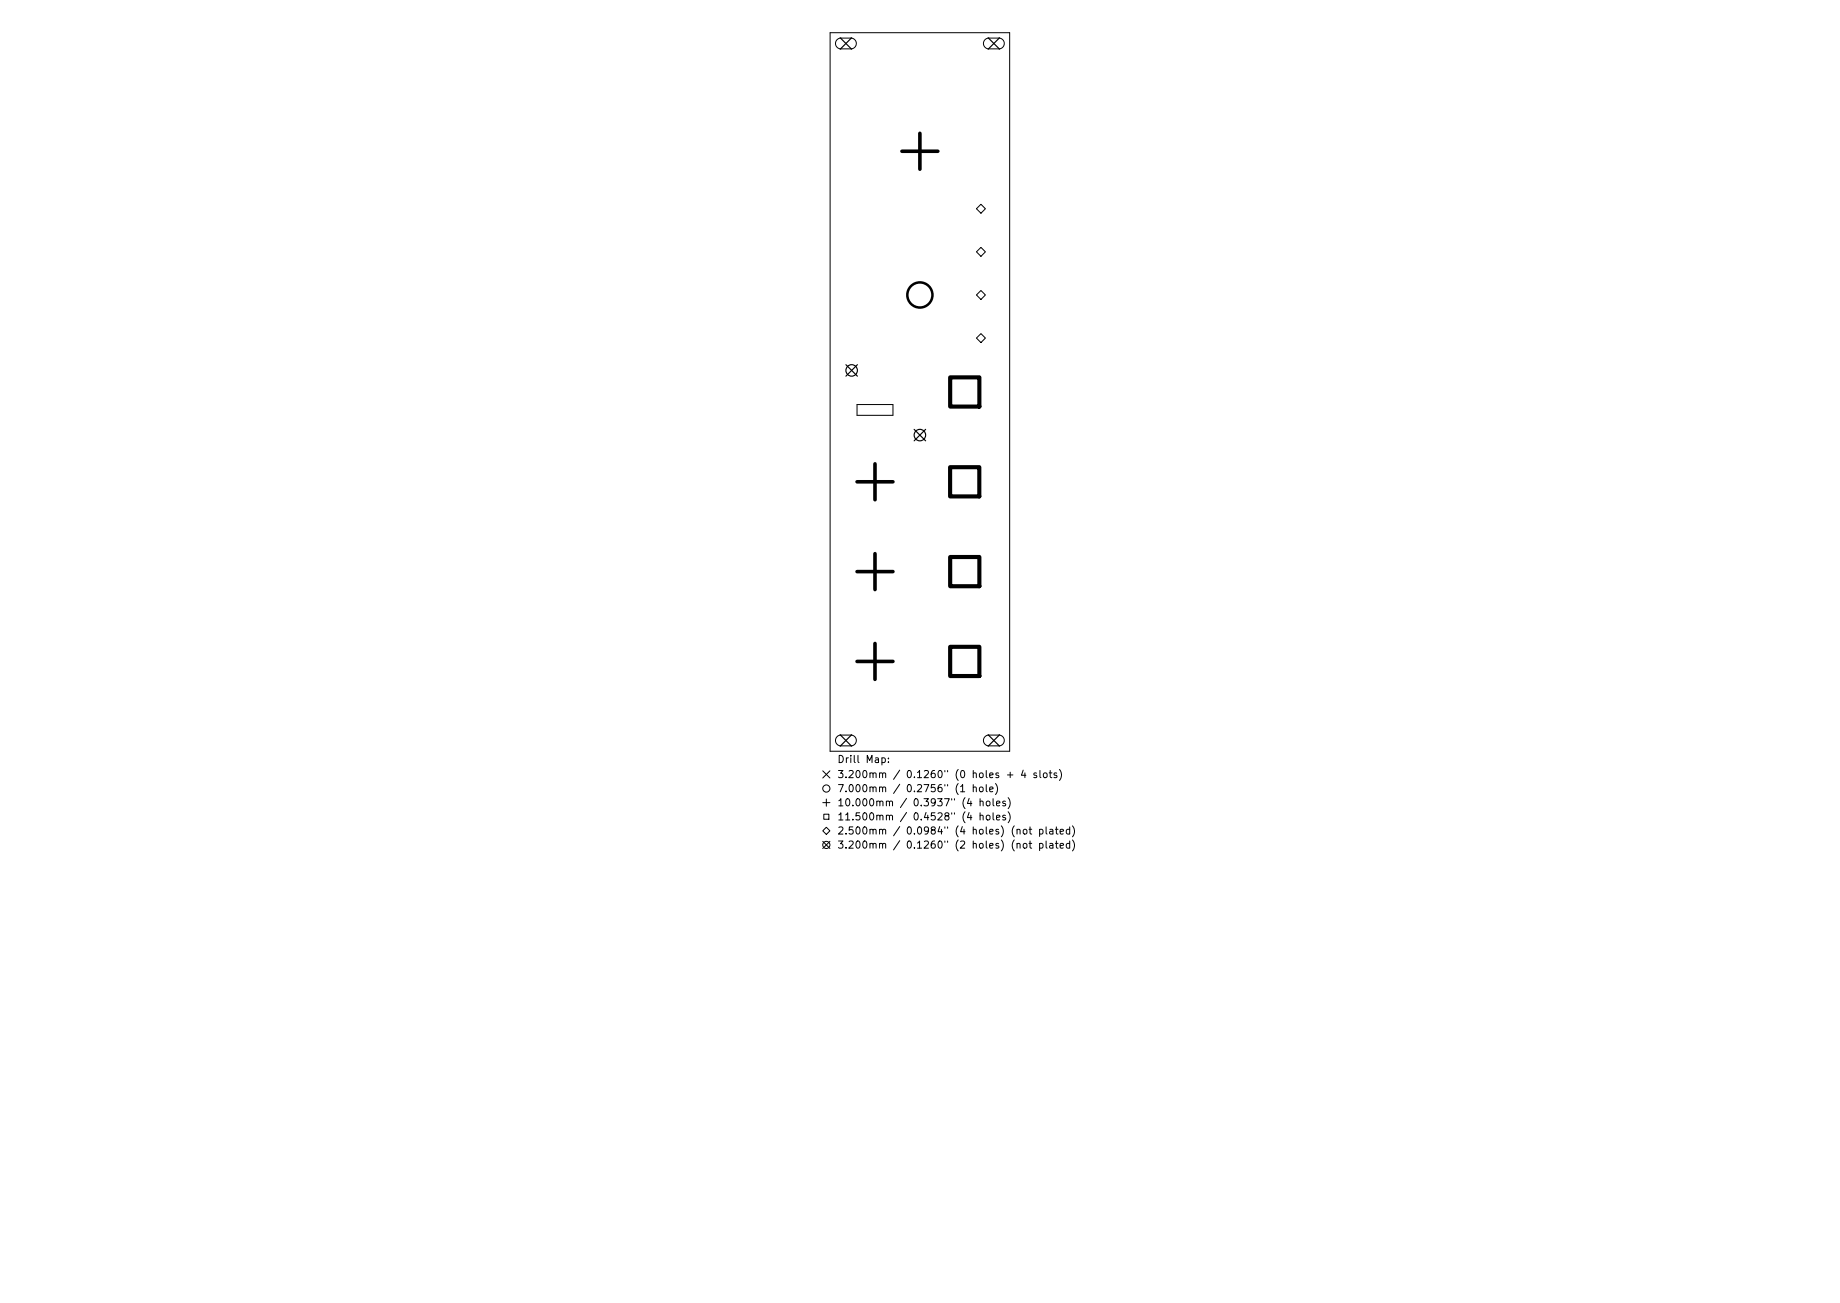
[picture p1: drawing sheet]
<svg xmlns="http://www.w3.org/2000/svg" width="297mm" height="210mm" viewBox="0 0 297 210" stroke-linecap="round" stroke-linejoin="round" font-family="sans-serif">
<defs><g id="words">
<g font-size="1.6">
<text x="135.1" y="123.1">Drill Map:</text>
<text x="135.1" y="125.5">3.200mm / 0.1260&quot; (0 holes + 4 slots)</text>
<text x="135.1" y="127.8">7.000mm / 0.2756&quot; (1 hole)</text>
<text x="135.1" y="130.1">10.000mm / 0.3937&quot; (4 holes)</text>
<text x="135.1" y="132.4">11.500mm / 0.4528&quot; (4 holes)</text>
<text x="135.1" y="134.6">2.500mm / 0.0984&quot; (4 holes) (not plated)</text>
<text x="135.1" y="136.9">3.200mm / 0.1260&quot; (2 holes) (not plated)</text>
</g>
</g></defs>
<g fill="none" stroke="#000" stroke-width=".16">
<path d="M134 5.3h29v115.9h-29zM135.1 6.4l.6-.2 1.7-.1a.87 .87 0 0 1 .8 .9 .87 .87 0 0 1-.8 .9h-1.7a.87 .87 0 0 1-.8-.6 .87 .87 0 0 1 .2-.9zM159 6.4l.6-.2 1.7-.1a.87 .87 0 0 1 .8 .9 .87 .87 0 0 1-.8 .9h-1.7a.87 .87 0 0 1-.8-.6 .87 .87 0 0 1 .2-.9zM158.4 33l.7 .7-.7 .7-.8-.7zM158.4 39.9l.7 .7-.7 .8-.8-.8zM157.6 54.6l.8-.8 .7 .8-.7 .7zM158.4 46.9l.7 .7-.7 .7-.8-.7zM138.4 65.3h5.8v1.7h-5.8zM135.1 118.9l.6-.3h1.7a.87 .87 0 0 1 .8 .9 .87 .87 0 0 1-.8 .9h-1.7a.87 .87 0 0 1-.8-.6 .87 .87 0 0 1 .2-.9zM159 118.9l.6-.3h1.7a.87 .87 0 0 1 .8 .9 .87 .87 0 0 1-.8 .9h-1.7a.87 .87 0 0 1-.8-.6 .87 .87 0 0 1 .2-.9zM132.8 124.4l1.2 1.1M132.8 129.5h1.2"/>
<path d="M132.8 135.8l1.2 1.1M133 131.4h.8v.8h-.8zM133.4 133.5l.6 .6-.6 .5-.6-.5zM133.4 128.9v1.2M134 124.4l-1.2 1.1M134 135.8l-1.2 1.1M142.4 122.3h.3l.2 .2-.1 .5h-.4M143.4 122.9v.2M143.4 122.3v.1M155.1 126.9l.3-.3v1.2M155.1 127.8h.6M156.5 128.8l-.3 .9h.7"/>
<path d="M156.5 131.1l-.3 .8h.7M157.1 127.1l.2-.1h.3v.8M157.1 126.6v1.2M158.2 127.1l.1-.1 .4 .1v.4l-.1 .2-.3 .1-.1-.1zM158.2 129.4l.2-.1h.3v.7M158.2 131.7l.2-.2 .3 .1v.7M158.2 128.9v1.1M158.2 131.2v1.1M159.2 126.6v1l.2 .2M159.3 129.3h.3l.2 .2v.3l-.2 .2h-.3l-.1-.2zM159.3 131.6l.3-.1 .2 .3v.3l-.2 .2h-.3l-.1-.2zM159.8 127.4l.5-.1v-.3h-.4l-.1 .2v.5h.5"/>
<path d="M160.3 128.9v1l.2 .1M160.3 131.2v.9l.2 .2M160.7 126.4a1.33 1.33 0 0 1 0 1.8M160.9 129.7l.5-.2v-.2h-.4l-.1 .1v.6h.5M160.9 131.9l.5-.1v-.2l-.4-.1-.1 .2v.6h.5M162.3 129.3h-.3l-.1 .1v.2l.4 .1v.3h-.4M162.3 131.6l-.3-.1-.1 .2v.2l.4 .1v.3h-.4M162.6 125h.9M162.7 128.7a1.33 1.33 0 0 1 0 1.8M162.7 131a1.33 1.33 0 0 1 0 1.8M163.1 124.6v.9M164.2 133.9l.1-.1 .3 .1 .1 .7"/>
<path d="M164.2 136.2l.1-.1h.3l.1 .8M165.2 124.3l-.3 .8h.7M165.2 133.9l.2-.1 .3 .1 .1 .5-.1 .1-.3 .1-.2-.1zM165.2 136.2l.2-.1 .3 .1 .1 .4-.1 .2-.3 .1-.2-.1zM165.5 124.7v.8M166.1 133.8h.5M166.1 136.1h.5M166.3 133.4v1l.3 .2M166.3 135.7v1l.3 .2M167.3 124.8l-.2-.1-.2 .2v.1l.4 .2v.2h-.4M167.8 133.9l.4-.1 .2 .2-.1 .5h-.5M167.8 136.1h.4l.2 .2-.1 .5h-.5"/>
<path d="M167.8 133.8v1.2M167.8 136.1v1.2M167.9 124.3v1l.1 .2M168.5 124.8l.2-.1 .3 .1v.5l-.1 .1-.2 .1-.2-.1zM168.9 133.4v1l.1 .2M168.9 135.7v1l.1 .2M169.4 124.7h.4M169.5 133.9h.4l.1 .7M169.5 136.1h.4l.1 .8M169.5 124.3v1l.3 .2M170 134.1h-.4l-.2 .2 .2 .3 .4-.1M170 136.4h-.4l-.2 .2 .2 .3 .4-.1"/>
<path d="M170.4 133.8h.4M170.4 136.1h.4M170.5 133.4v1l.3 .2M170.5 135.7v1l.3 .2M170.6 124.8l-.3-.1-.2 .2 .1 .1 .4 .2v.2h-.5M171 124.2a1.33 1.33 0 0 1 0 1.7M171.1 134.2l.6-.1-.1-.2-.3-.1-.2 .2 .1 .5h.4M171.1 136.5l.6-.1-.1-.3h-.3l-.2 .2 .1 .5h.4M172.7 133.9l-.3-.1-.3 .2 .1 .5h.5M172.7 136.1h-.3l-.3 .2 .1 .5h.5M172.7 133.4v1.2M172.7 135.7v1.2"/>
<path d="M173.1 133.3a1.33 1.33 0 0 1 0 1.7M173.1 135.5a1.33 1.33 0 0 1 0 1.8"/>
<circle cx="133.4" cy="136.3" r=".58"/>
<circle cx="133.4" cy="127.2" r=".58"/>
</g>
<g fill="none" stroke="#000" stroke-width=".19">
<path d="M135.6 6.1l1.9 1.8M137.5 6.1l-1.9 1.8M159.5 6.1l1.9 1.8M161.4 6.1l-1.9 1.8M136.6 58.8l1.8 1.9M138.4 58.8l-1.8 1.9M147.6 69.3l1.8 1.8M149.4 69.3l-1.8 1.8M135.6 118.6l1.9 1.8M137.5 118.6l-1.9 1.8M159.5 118.6l1.9 1.8M161.4 118.6l-1.9 1.8"/>
<circle cx="137.5" cy="59.8" r=".93"/>
<circle cx="148.5" cy="70.2" r=".93"/>
</g>
<circle cx="148.5" cy="47.6" r="2.03" fill="none" stroke="#000" stroke-width=".41"/>
<path d="M145.6 24.4h5.8M148.5 21.5v5.8M138.4 77.7h5.8M141.3 74.8v5.8M138.4 92.2h5.8M141.3 89.3v5.8M138.4 106.7h5.8M141.3 103.8v5.8" fill="none" stroke="#000" stroke-width=".58"/>
<path d="M153.4 75.4h4.7v4.7h-4.7zM153.4 60.9h4.7v4.7h-4.7zM153.4 89.9h4.7v4.7h-4.7zM153.4 104.4h4.7v4.7h-4.7z" fill="none" stroke="#000" stroke-width=".67"/>
<use href="#words"/>
</svg>
